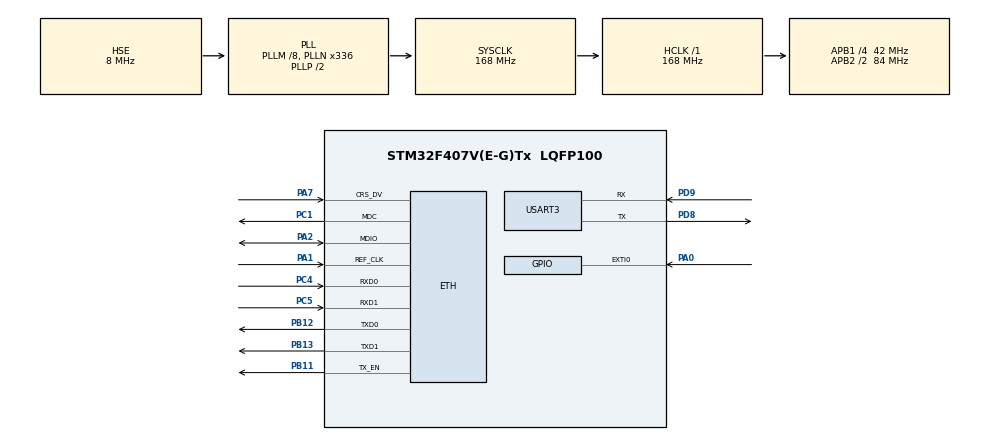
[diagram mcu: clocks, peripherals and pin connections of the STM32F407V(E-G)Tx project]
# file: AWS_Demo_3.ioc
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ETH.MediaInterface=ETH_MEDIA_INTERFACE_RMII
FREERTOS.Tasks01=defaultTask,0,128,StartDefaultTask,Default,NULL
LWIP.IP_ADDRESS=198.168.137.101
LWIP.LWIP_DHCP=0
LWIP.NETMASK_ADDRESS=255.255.255.000
LWIP.Version=v2.0.3_Cube
Mcu.Family=STM32F4
Mcu.Name=STM32F407V(E-G)Tx
Mcu.Package=LQFP100
NVIC.EXTI0_IRQn=true\:5\:0\:false\:false\:true\:true\:true\:true
NVIC.PriorityGroup=NVIC_PRIORITYGROUP_4
NVIC.TIM3_IRQn=true\:0\:0\:false\:false\:true\:false\:false\:true
NVIC.TimeBase=TIM3_IRQn
NVIC.TimeBaseIP=TIM3
PA0-WKUP.Signal=GPXTI0
PA1.Mode=RMII
PA1.Signal=ETH_REF_CLK
PA2.Mode=RMII
PA2.Signal=ETH_MDIO
PA7.Mode=RMII
PA7.Signal=ETH_CRS_DV
PB11.Mode=RMII
PB11.Signal=ETH_TX_EN
PB12.Mode=RMII
PB12.Signal=ETH_TXD0
PB13.Mode=RMII
PB13.Signal=ETH_TXD1
PC1.Mode=RMII
PC1.Signal=ETH_MDC
PC14-OSC32_IN.Mode=LSE-External-Oscillator
PC14-OSC32_IN.Signal=RCC_OSC32_IN
PC15-OSC32_OUT.Mode=LSE-External-Oscillator
PC15-OSC32_OUT.Signal=RCC_OSC32_OUT
PC4.Mode=RMII
PC4.Signal=ETH_RXD0
PC5.Mode=RMII
PC5.Signal=ETH_RXD1
PD8.Mode=Asynchronous
PD8.Signal=USART3_TX
PD9.Mode=Asynchronous
PD9.Signal=USART3_RX
PH0-OSC_IN.Mode=HSE-External-Oscillator
PH0-OSC_IN.Signal=RCC_OSC_IN
PH1-OSC_OUT.Mode=HSE-External-Oscillator
PH1-OSC_OUT.Signal=RCC_OSC_OUT
ProjectManager.HeapSize=0x200
ProjectManager.StackSize=0x400
ProjectManager.TargetToolchain=SW4STM32
RCC.48MHZClocksFreq_Value=48000000
RCC.AHBFreq_Value=168000000
RCC.APB1CLKDivider=RCC_HCLK_DIV4
RCC.APB1Freq_Value=42000000
RCC.APB1TimFreq_Value=84000000
RCC.APB2CLKDivider=RCC_HCLK_DIV2
RCC.APB2Freq_Value=84000000
RCC.APB2TimFreq_Value=168000000
RCC.CortexFreq_Value=168000000
RCC.HCLKFreq_Value=168000000
RCC.HSE_VALUE=8000000
RCC.HSI_VALUE=16000000
RCC.PLLM=8
RCC.PLLN=336
RCC.PLLQ=7
RCC.PLLSourceVirtual=RCC_PLLSOURCE_HSE
RCC.SYSCLKFreq_VALUE=168000000
RCC.SYSCLKSource=RCC_SYSCLKSOURCE_PLLCLK
RCC.VCOOutputFreq_Value=336000000
USART3.VirtualMode=VM_ASYNC
VP_FREERTOS_VS_CMSIS_V1.Mode=CMSIS_V1
VP_LWIP_VS_Enabled.Mode=Enabled
VP_MBEDTLS_VS_MBEDTLS.Mode=Enabled
VP_RNG_VS_RNG.Mode=RNG_Activate
VP_RTC_VS_RTC_Activate.Mode=RTC_Enabled
VP_RTC_VS_RTC_Calendar.Mode=RTC_Calendar
VP_SYS_VS_tim3.Mode=TIM3
VP_TIM2_VS_ClockSourceINT.Mode=Internal
VP_TIM4_VS_ClockSourceINT.Mode=Internal
board=STM32F4DISCOVERY

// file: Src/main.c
/* USER CODE BEGIN Header */
/**
  ******************************************************************************
  * @file           : main.c
  * @brief          : Main program body
  ******************************************************************************
  * @attention
  *
  * <h2><center>&copy; Copyright (c) 2019 STMicroelectronics.
  * All rights reserved.</center></h2>
  *
  * This software component is licensed by ST under Ultimate Liberty license
  * SLA0044, the "License"; You may not use this file except in compliance with
  * the License. You may obtain a copy of the License at:
  *                             www.st.com/SLA0044
  *
  ******************************************************************************
  */
/* USER CODE END Header */

#include "main.h"
#include "cmsis_os.h"

/* USER CODE BEGIN Includes */
int counter_2=0;

/* USER CODE END Includes */

/* USER CODE BEGIN PTD */
//#define CCMRAM_HEAP_SIZE  64000
//#define RAM_HEAP_SIZE    78445
//char memblock1 [RAM_HEAP_SIZE];
//__attribute__((section(".ccmram")))
//char memblock2[CCMRAM_HEAP_SIZE];

/* USER CODE END PTD */

/* USER CODE BEGIN PD */
 // HeapRegion_t xHeapRegions[] =
 // {
  	//{ ( uint8_t * ) memblock2, CCMRAM_HEAP_SIZE },// << Defines a block of 0x10000 bytes starting at address 0x80000000
  	//{ ( uint8_t * )memblock1, RAM_HEAP_SIZE }, //<< Defines a block of 0xa0000 bytes starting at address of 0x90000000
  	//{ NULL, 0 }              //  << Terminates the array.
  //};
/* USER CODE END PD */

RNG_HandleTypeDef hrng;

RTC_HandleTypeDef hrtc;

TIM_HandleTypeDef htim2;
TIM_HandleTypeDef htim4;

UART_HandleTypeDef huart3;

osThreadId defaultTaskHandle;
/* USER CODE BEGIN PV */
net_hnd_t         hnet; /* Is initialized by cloud_main(). */
/* USER CODE END PV */

void SystemClock_Config(void);
static void MX_GPIO_Init(void);
static void MX_RTC_Init(void);
static void MX_TIM2_Init(void);
static void MX_TIM4_Init(void);
static void MX_USART3_UART_Init(void);
static void MX_RNG_Init(void);
void StartDefaultTask(void const * argument);

/* USER CODE BEGIN PFP */
static void cloud_test(void const *arg);
static void Button_ISR(void);

/* USER CODE END PFP */

/* USER CODE BEGIN 0 */
static volatile uint8_t button_flags = 0;

void vApplicationMallocFailedHook(){
	for(;;){
		vTaskDelay(pdMS_TO_TICKS(1000));
		printf(" vApplicationMallocFailedHook\n\r");
	}
}

void vApplicationStackOverflowHook( TaskHandle_t xTask, char *pcTaskName ){
	for(;;){
		vTaskDelay(pdMS_TO_TICKS(1000));
		printf(" vApplicationStackOverflowHook\n\r");

	}
}
/* USER CODE END 0 */

int main(void)
{

  /* MCU Configuration--------------------------------------------------------*/

  /* Reset of all peripherals, Initializes the Flash interface and the Systick. */

	  HAL_Init();

  /* Configure the system clock */
  SystemClock_Config();

  /* Initialize all configured peripherals */
  MX_GPIO_Init();
  MX_RTC_Init();
  MX_TIM2_Init();
  MX_TIM4_Init();
  MX_USART3_UART_Init();
  MX_RNG_Init();
  /* USER CODE BEGIN 2 */
 //vPortDefineHeapRegions( xHeapRegions);

  /* USER CODE END 2 */

  /* Create the thread(s) */
  /* definition and creation of defaultTask */
  osThreadDef(defaultTask, StartDefaultTask, osPriorityNormal, 0, 128);
  defaultTaskHandle = osThreadCreate(osThread(defaultTask), NULL);

  /* USER CODE BEGIN RTOS_THREADS */
  /* add threads, ... */
  printf("\r\nhello world \r\n");
  /* USER CODE END RTOS_THREADS */

  /* Start scheduler */
  osKernelStart();

  /* We should never get here as control is now taken by the scheduler */

  /* Infinite loop */
  while (1)
  {

  }
}

void SystemClock_Config(void)
{
  RCC_OscInitTypeDef RCC_OscInitStruct = {0};
  RCC_ClkInitTypeDef RCC_ClkInitStruct = {0};
  RCC_PeriphCLKInitTypeDef PeriphClkInitStruct = {0};

  /** Configure the main internal regulator output voltage
  */
  __HAL_RCC_PWR_CLK_ENABLE();
  __HAL_PWR_VOLTAGESCALING_CONFIG(PWR_REGULATOR_VOLTAGE_SCALE1);
  /** Initializes the CPU, AHB and APB busses clocks
  */
  RCC_OscInitStruct.OscillatorType = RCC_OSCILLATORTYPE_LSI|RCC_OSCILLATORTYPE_HSE;
  RCC_OscInitStruct.HSEState = RCC_HSE_ON;
  RCC_OscInitStruct.LSIState = RCC_LSI_ON;
  RCC_OscInitStruct.PLL.PLLState = RCC_PLL_ON;
  RCC_OscInitStruct.PLL.PLLSource = RCC_PLLSOURCE_HSE;
  RCC_OscInitStruct.PLL.PLLM = 8;
  RCC_OscInitStruct.PLL.PLLN = 336;
  RCC_OscInitStruct.PLL.PLLP = RCC_PLLP_DIV2;
  RCC_OscInitStruct.PLL.PLLQ = 7;
  if (HAL_RCC_OscConfig(&RCC_OscInitStruct) != HAL_OK)
  {
    Error_Handler();
  }
  /** Initializes the CPU, AHB and APB busses clocks
  */
  RCC_ClkInitStruct.ClockType = RCC_CLOCKTYPE_HCLK|RCC_CLOCKTYPE_SYSCLK
                              |RCC_CLOCKTYPE_PCLK1|RCC_CLOCKTYPE_PCLK2;
  RCC_ClkInitStruct.SYSCLKSource = RCC_SYSCLKSOURCE_PLLCLK;
  RCC_ClkInitStruct.AHBCLKDivider = RCC_SYSCLK_DIV1;
  RCC_ClkInitStruct.APB1CLKDivider = RCC_HCLK_DIV4;
  RCC_ClkInitStruct.APB2CLKDivider = RCC_HCLK_DIV2;

  if (HAL_RCC_ClockConfig(&RCC_ClkInitStruct, FLASH_LATENCY_5) != HAL_OK)
  {
    Error_Handler();
  }
  PeriphClkInitStruct.PeriphClockSelection = RCC_PERIPHCLK_RTC;
  PeriphClkInitStruct.RTCClockSelection = RCC_RTCCLKSOURCE_LSI;
  if (HAL_RCCEx_PeriphCLKConfig(&PeriphClkInitStruct) != HAL_OK)
  {
    Error_Handler();
  }
}

static void MX_RNG_Init(void)
{

  hrng.Instance = RNG;
  if (HAL_RNG_Init(&hrng) != HAL_OK)
  {
    Error_Handler();
  }

}

static void MX_RTC_Init(void)
{

  RTC_TimeTypeDef sTime = {0};
  RTC_DateTypeDef sDate = {0};

  /** Initialize RTC Only
  */
  hrtc.Instance = RTC;
  hrtc.Init.HourFormat = RTC_HOURFORMAT_24;
  hrtc.Init.AsynchPrediv = 127;
  hrtc.Init.SynchPrediv = 255;
  hrtc.Init.OutPut = RTC_OUTPUT_DISABLE;
  hrtc.Init.OutPutPolarity = RTC_OUTPUT_POLARITY_HIGH;
  hrtc.Init.OutPutType = RTC_OUTPUT_TYPE_OPENDRAIN;
  if (HAL_RTC_Init(&hrtc) != HAL_OK)
  {
    Error_Handler();
  }

  /** Initialize RTC and set the Time and Date
  */
  sTime.Hours = 0x0;
  sTime.Minutes = 0x0;
  sTime.Seconds = 0x0;
  sTime.DayLightSaving = RTC_DAYLIGHTSAVING_NONE;
  sTime.StoreOperation = RTC_STOREOPERATION_RESET;
  if (HAL_RTC_SetTime(&hrtc, &sTime, RTC_FORMAT_BCD) != HAL_OK)
  {
    Error_Handler();
  }
  sDate.WeekDay = RTC_WEEKDAY_MONDAY;
  sDate.Month = RTC_MONTH_JANUARY;
  sDate.Date = 0x1;
  sDate.Year = 0x0;

  if (HAL_RTC_SetDate(&hrtc, &sDate, RTC_FORMAT_BCD) != HAL_OK)
  {
    Error_Handler();
  }

}

static void MX_TIM2_Init(void)
{

  TIM_ClockConfigTypeDef sClockSourceConfig = {0};
  TIM_MasterConfigTypeDef sMasterConfig = {0};

  htim2.Instance = TIM2;
  htim2.Init.Prescaler = 0;
  htim2.Init.CounterMode = TIM_COUNTERMODE_UP;
  htim2.Init.Period = 0;
  htim2.Init.ClockDivision = TIM_CLOCKDIVISION_DIV1;
  htim2.Init.AutoReloadPreload = TIM_AUTORELOAD_PRELOAD_DISABLE;
  if (HAL_TIM_Base_Init(&htim2) != HAL_OK)
  {
    Error_Handler();
  }
  sClockSourceConfig.ClockSource = TIM_CLOCKSOURCE_INTERNAL;
  if (HAL_TIM_ConfigClockSource(&htim2, &sClockSourceConfig) != HAL_OK)
  {
    Error_Handler();
  }
  sMasterConfig.MasterOutputTrigger = TIM_TRGO_RESET;
  sMasterConfig.MasterSlaveMode = TIM_MASTERSLAVEMODE_DISABLE;
  if (HAL_TIMEx_MasterConfigSynchronization(&htim2, &sMasterConfig) != HAL_OK)
  {
    Error_Handler();
  }

}

static void MX_TIM4_Init(void)
{

  TIM_ClockConfigTypeDef sClockSourceConfig = {0};
  TIM_MasterConfigTypeDef sMasterConfig = {0};

  htim4.Instance = TIM4;
  htim4.Init.Prescaler = 0;
  htim4.Init.CounterMode = TIM_COUNTERMODE_UP;
  htim4.Init.Period = 0;
  htim4.Init.ClockDivision = TIM_CLOCKDIVISION_DIV1;
  htim4.Init.AutoReloadPreload = TIM_AUTORELOAD_PRELOAD_DISABLE;
  if (HAL_TIM_Base_Init(&htim4) != HAL_OK)
  {
    Error_Handler();
  }
  sClockSourceConfig.ClockSource = TIM_CLOCKSOURCE_INTERNAL;
  if (HAL_TIM_ConfigClockSource(&htim4, &sClockSourceConfig) != HAL_OK)
  {
    Error_Handler();
  }
  sMasterConfig.MasterOutputTrigger = TIM_TRGO_RESET;
  sMasterConfig.MasterSlaveMode = TIM_MASTERSLAVEMODE_DISABLE;
  if (HAL_TIMEx_MasterConfigSynchronization(&htim4, &sMasterConfig) != HAL_OK)
  {
    Error_Handler();
  }

}

static void MX_USART3_UART_Init(void)
{

  huart3.Instance = USART3;
  huart3.Init.BaudRate = 115200;
  huart3.Init.WordLength = UART_WORDLENGTH_8B;
  huart3.Init.StopBits = UART_STOPBITS_1;
  huart3.Init.Parity = UART_PARITY_NONE;
  huart3.Init.Mode = UART_MODE_TX_RX;
  huart3.Init.HwFlowCtl = UART_HWCONTROL_NONE;
  huart3.Init.OverSampling = UART_OVERSAMPLING_16;
  if (HAL_UART_Init(&huart3) != HAL_OK)
  {
    Error_Handler();
  }

}

static void MX_GPIO_Init(void)
{
  GPIO_InitTypeDef GPIO_InitStruct = {0};

  /* GPIO Ports Clock Enable */
  __HAL_RCC_GPIOC_CLK_ENABLE();
  __HAL_RCC_GPIOH_CLK_ENABLE();
  __HAL_RCC_GPIOA_CLK_ENABLE();
  __HAL_RCC_GPIOB_CLK_ENABLE();
  __HAL_RCC_GPIOD_CLK_ENABLE();

  /*Configure GPIO pin : PA0 */
  GPIO_InitStruct.Pin = GPIO_PIN_0;
  GPIO_InitStruct.Mode = GPIO_MODE_IT_RISING;
  GPIO_InitStruct.Pull = GPIO_NOPULL;
  HAL_GPIO_Init(GPIOA, &GPIO_InitStruct);
  GPIO_InitStruct.Pin = GPIO_PIN_12;
  GPIO_InitStruct.Mode = GPIO_MODE_OUTPUT_PP;
  GPIO_InitStruct.Pull = GPIO_NOPULL;
  HAL_GPIO_Init(GPIOD, &GPIO_InitStruct);
  GPIO_InitStruct.Pin = GPIO_PIN_13;
  GPIO_InitStruct.Mode = GPIO_MODE_OUTPUT_PP;
  GPIO_InitStruct.Pull = GPIO_NOPULL;
  HAL_GPIO_Init(GPIOD, &GPIO_InitStruct);
  GPIO_InitStruct.Pin = GPIO_PIN_14;
  GPIO_InitStruct.Mode = GPIO_MODE_OUTPUT_PP;
  GPIO_InitStruct.Pull = GPIO_NOPULL;
  HAL_GPIO_Init(GPIOD, &GPIO_InitStruct);
  GPIO_InitStruct.Pin = GPIO_PIN_15;
  GPIO_InitStruct.Mode = GPIO_MODE_OUTPUT_PP;
  GPIO_InitStruct.Pull = GPIO_NOPULL;
  HAL_GPIO_Init(GPIOD, &GPIO_InitStruct);
  /* EXTI interrupt init*/
  HAL_NVIC_SetPriority(EXTI0_IRQn, 6, 0);
  HAL_NVIC_EnableIRQ(EXTI0_IRQn);

}

/* USER CODE BEGIN 4 */

#if (defined(__GNUC__) && !defined(__CC_ARM))
/* With GCC/RAISONANCE, small printf (option LD Linker->Libraries->Small printf
   set to 'Yes') calls __io_putchar() */
#define PUTCHAR_PROTOTYPE int __io_putchar(int ch)
#define GETCHAR_PROTOTYPE int __io_getchar(void)
#else
#define PUTCHAR_PROTOTYPE int fputc(int ch, FILE *f)
#define GETCHAR_PROTOTYPE int fgetc(FILE *f)
#endif /* __GNUC__ */

/**
  * @brief  Retargets the C library printf function to the USART.
  * @param  None
  * @retval None
  */
PUTCHAR_PROTOTYPE
{
  /* Place your implementation of fputc here */
  /* e.g. write a character to the USART2 and Loop until the end of transmission */
  while (HAL_OK != HAL_UART_Transmit(&huart3, (uint8_t *) &ch, 1, 30000))
  {
    ;
  }
  return ch;
}

/**
  * @brief  Retargets the C library scanf function to the USART.
  * @param  None
  * @retval None
  */
GETCHAR_PROTOTYPE
{
  /* Place your implementation of fgetc here */
  /* e.g. read a character on USART and loop until the end of read */
  uint8_t ch = 0;
  while (HAL_OK != HAL_UART_Receive(&huart3, (uint8_t *)&ch, 1, 30000))
  {
    ;
  }
  return ch;
}
static void cloud_test(void const *arg)
{
  platform_init();
  subscribe_publish_sensor_values();
  platform_deinit();
}

/**
  * @brief Update button ISR status
  */
static void Button_ISR(void)
{
  button_flags++;
}
/**
  * @brief Set LED state
  */
void Led_SetState(bool on)
{
  if (on == true)
  {
    HAL_GPIO_WritePin(GPIOD,GPIO_PIN_15,GPIO_PIN_SET);
  }
  else
  {
	 HAL_GPIO_WritePin(GPIOD,GPIO_PIN_15,GPIO_PIN_RESET);
  }
}

/**
  * @brief  EXTI line detection callback.
  * @param  GPIO_Pin: Specifies the port pin connected to corresponding EXTI line.
  * @retval None
  */
void HAL_GPIO_EXTI_Callback(uint16_t GPIO_Pin)
{
  switch (GPIO_Pin)
  {
    case (GPIO_PIN_0):
    {
      Button_ISR();
      break;
    }

    default:
    {
      break;
    }
  }
}

/**
  * @brief Waiting for button to be pushed
  */
uint8_t Button_WaitForPush(uint32_t delay)
{
  uint32_t time_out = HAL_GetTick()+delay;
  do
  {
    if (button_flags > 1)
    {
      button_flags = 0;
      return BP_MULTIPLE_PUSH;
    }

    if (button_flags == 1)
    {
      button_flags = 0;
      return BP_SINGLE_PUSH;
    }
  }
  while( HAL_GetTick() < time_out);
  return BP_NOT_PUSHED;
}

/**
  * @brief Waiting for button to be pushed
  */
uint8_t Button_WaitForMultiPush(uint32_t delay)
{
  HAL_Delay(delay);
  if (button_flags > 1)
  {
    button_flags = 0;
    return BP_MULTIPLE_PUSH;
  }

  if (button_flags == 1)
  {
    button_flags = 0;
    return BP_SINGLE_PUSH;
  }
  return BP_NOT_PUSHED;
}

/* USER CODE END 4 */

void StartDefaultTask(void const * argument)
{
  /* MX_LWIP_Init() is generated within mbedtls_net_init() function in net_cockets.c file */
  /* Up to user to call mbedtls_net_init() function in MBEDTLS initialization step */

  /* Up to user define the empty MX_MBEDTLS_Init() function located in mbedtls.c file */

  /* USER CODE BEGIN 5 */
	  UNUSED(argument);
	 msg_info("\r\n Starting Main Thread...\n");
	  /* Start application task */
	  /* Beware that the OS stack frames are allocated from the OS heap. May incur RAM overwrite in case of overflow. */
	  osThreadDef(CLOUDNAME, &cloud_test, osPriorityNormal, 0,  ((3*1024)));
	  osThreadCreate (osThread(CLOUDNAME), NULL);
  /* Infinite loop */
  for(;;)
  {
	   osThreadTerminate(NULL);

  }
  /* USER CODE END 5 */
}

void HAL_TIM_PeriodElapsedCallback(TIM_HandleTypeDef *htim)
{
  if (htim->Instance == TIM3) {
    HAL_IncTick();
  }
  /* USER CODE BEGIN Callback 1 */
  /* else if (htim->Instance == TIM4) {
(int) xFreeBytesRemaning;
    printf("xfreeBytes=%d",y );
  } */
  /* USER CODE END Callback 1 */
}

void Error_Handler(void)
{
}

/************************ (C) COPYRIGHT STMicroelectronics *****END OF FILE****/
